VERSION 5.7 ;
  NOWIREEXTENSIONATPIN ON ;
  DIVIDERCHAR "/" ;
  BUSBITCHARS "[]" ;
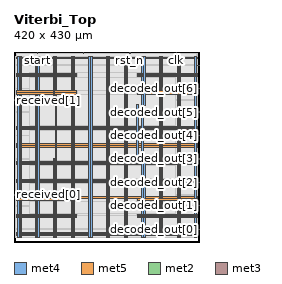
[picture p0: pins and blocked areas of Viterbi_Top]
MACRO Viterbi_Top
  CLASS BLOCK ;
  FOREIGN Viterbi_Top ;
  ORIGIN 0.000 0.000 ;
  SIZE 420.000 BY 430.000 ;
  PIN VGND
    DIRECTION INOUT ;
    USE GROUND ;
    PORT
      LAYER met4 ;
        RECT 13.720 10.640 16.720 419.120 ;
    END
    PORT
      LAYER met4 ;
        RECT 53.720 10.640 56.720 419.120 ;
    END
    PORT
      LAYER met4 ;
        RECT 93.720 10.640 96.720 419.120 ;
    END
    PORT
      LAYER met4 ;
        RECT 133.720 10.640 136.720 419.120 ;
    END
    PORT
      LAYER met4 ;
        RECT 173.720 10.640 176.720 419.120 ;
    END
    PORT
      LAYER met4 ;
        RECT 213.720 10.640 216.720 419.120 ;
    END
    PORT
      LAYER met4 ;
        RECT 253.720 10.640 256.720 419.120 ;
    END
    PORT
      LAYER met4 ;
        RECT 293.720 10.640 296.720 189.380 ;
    END
    PORT
      LAYER met4 ;
        RECT 293.720 308.540 296.720 419.120 ;
    END
    PORT
      LAYER met4 ;
        RECT 333.720 10.640 336.720 419.120 ;
    END
    PORT
      LAYER met4 ;
        RECT 373.720 10.640 376.720 419.120 ;
    END
    PORT
      LAYER met5 ;
        RECT 5.280 19.080 414.700 22.080 ;
    END
    PORT
      LAYER met5 ;
        RECT 5.280 59.080 141.420 62.080 ;
    END
    PORT
      LAYER met5 ;
        RECT 5.280 99.080 414.700 102.080 ;
    END
    PORT
      LAYER met5 ;
        RECT 5.280 139.080 414.700 142.080 ;
    END
    PORT
      LAYER met5 ;
        RECT 5.280 179.080 414.700 182.080 ;
    END
    PORT
      LAYER met5 ;
        RECT 5.280 219.080 414.700 222.080 ;
    END
    PORT
      LAYER met5 ;
        RECT 5.280 259.080 414.700 262.080 ;
    END
    PORT
      LAYER met5 ;
        RECT 5.280 339.080 141.420 342.080 ;
    END
    PORT
      LAYER met5 ;
        RECT 5.280 379.080 141.420 382.080 ;
    END
    PORT
      LAYER met5 ;
        RECT 278.400 59.080 414.700 62.080 ;
    END
    PORT
      LAYER met5 ;
        RECT 278.400 339.080 414.700 342.080 ;
    END
    PORT
      LAYER met5 ;
        RECT 278.400 379.080 414.700 382.080 ;
    END
    PORT
      LAYER met4 ;
        RECT 277.720 184.720 280.720 310.320 ;
    END
  END VGND
  PIN VPWR
    DIRECTION INOUT ;
    USE POWER ;
    PORT
      LAYER met4 ;
        RECT 9.020 10.640 12.020 419.120 ;
    END
    PORT
      LAYER met4 ;
        RECT 49.020 10.640 52.020 419.120 ;
    END
    PORT
      LAYER met4 ;
        RECT 89.020 10.640 92.020 189.380 ;
    END
    PORT
      LAYER met4 ;
        RECT 89.020 308.540 92.020 419.120 ;
    END
    PORT
      LAYER met4 ;
        RECT 129.020 10.640 132.020 419.120 ;
    END
    PORT
      LAYER met4 ;
        RECT 169.020 10.640 172.020 419.120 ;
    END
    PORT
      LAYER met4 ;
        RECT 209.020 10.640 212.020 419.120 ;
    END
    PORT
      LAYER met4 ;
        RECT 249.020 10.640 252.020 419.120 ;
    END
    PORT
      LAYER met4 ;
        RECT 289.020 10.640 292.020 419.120 ;
    END
    PORT
      LAYER met4 ;
        RECT 329.020 10.640 332.020 419.120 ;
    END
    PORT
      LAYER met4 ;
        RECT 369.020 10.640 372.020 419.120 ;
    END
    PORT
      LAYER met4 ;
        RECT 409.020 10.640 412.020 419.120 ;
    END
    PORT
      LAYER met5 ;
        RECT 5.280 14.380 414.700 17.380 ;
    END
    PORT
      LAYER met5 ;
        RECT 5.280 54.380 141.420 57.380 ;
    END
    PORT
      LAYER met5 ;
        RECT 5.280 94.380 141.420 97.380 ;
    END
    PORT
      LAYER met5 ;
        RECT 5.280 134.380 414.700 137.380 ;
    END
    PORT
      LAYER met5 ;
        RECT 5.280 174.380 414.700 177.380 ;
    END
    PORT
      LAYER met5 ;
        RECT 5.280 214.380 414.700 217.380 ;
    END
    PORT
      LAYER met5 ;
        RECT 5.280 254.380 414.700 257.380 ;
    END
    PORT
      LAYER met5 ;
        RECT 5.280 334.380 141.420 337.380 ;
    END
    PORT
      LAYER met5 ;
        RECT 5.280 374.380 141.420 377.380 ;
    END
    PORT
      LAYER met5 ;
        RECT 5.280 414.380 414.700 417.380 ;
    END
    PORT
      LAYER met5 ;
        RECT 278.400 54.380 414.700 57.380 ;
    END
    PORT
      LAYER met5 ;
        RECT 278.400 94.380 414.700 97.380 ;
    END
    PORT
      LAYER met5 ;
        RECT 278.400 334.380 414.700 337.380 ;
    END
    PORT
      LAYER met5 ;
        RECT 278.400 374.380 414.700 377.380 ;
    END
  END VPWR
  PIN clk
    DIRECTION INPUT ;
    USE SIGNAL ;
    ANTENNAGATEAREA 1.286700 ;
    ANTENNADIFFAREA 0.434700 ;
    PORT
      LAYER met2 ;
        RECT 367.170 426.000 367.450 430.000 ;
    END
  END clk
  PIN decoded_out[0]
    DIRECTION OUTPUT ;
    USE SIGNAL ;
    ANTENNADIFFAREA 0.445500 ;
    PORT
      LAYER met3 ;
        RECT 416.000 28.600 420.000 29.200 ;
    END
  END decoded_out[0]
  PIN decoded_out[1]
    DIRECTION OUTPUT ;
    USE SIGNAL ;
    ANTENNADIFFAREA 0.445500 ;
    PORT
      LAYER met3 ;
        RECT 416.000 81.640 420.000 82.240 ;
    END
  END decoded_out[1]
  PIN decoded_out[2]
    DIRECTION OUTPUT ;
    USE SIGNAL ;
    ANTENNADIFFAREA 0.445500 ;
    PORT
      LAYER met3 ;
        RECT 416.000 134.680 420.000 135.280 ;
    END
  END decoded_out[2]
  PIN decoded_out[3]
    DIRECTION OUTPUT ;
    USE SIGNAL ;
    ANTENNADIFFAREA 0.445500 ;
    PORT
      LAYER met3 ;
        RECT 416.000 187.720 420.000 188.320 ;
    END
  END decoded_out[3]
  PIN decoded_out[4]
    DIRECTION OUTPUT ;
    USE SIGNAL ;
    ANTENNADIFFAREA 0.445500 ;
    PORT
      LAYER met3 ;
        RECT 416.000 240.760 420.000 241.360 ;
    END
  END decoded_out[4]
  PIN decoded_out[5]
    DIRECTION OUTPUT ;
    USE SIGNAL ;
    ANTENNADIFFAREA 0.445500 ;
    PORT
      LAYER met3 ;
        RECT 416.000 293.800 420.000 294.400 ;
    END
  END decoded_out[5]
  PIN decoded_out[6]
    DIRECTION OUTPUT ;
    USE SIGNAL ;
    ANTENNADIFFAREA 0.445500 ;
    PORT
      LAYER met3 ;
        RECT 416.000 346.840 420.000 347.440 ;
    END
  END decoded_out[6]
  PIN decoded_out[7]
    DIRECTION OUTPUT ;
    USE SIGNAL ;
    ANTENNADIFFAREA 0.445500 ;
    PORT
      LAYER met3 ;
        RECT 416.000 399.880 420.000 400.480 ;
    END
  END decoded_out[7]
  PIN frame_done
    DIRECTION OUTPUT ;
    USE SIGNAL ;
    ANTENNADIFFAREA 0.445500 ;
    PORT
      LAYER met2 ;
        RECT 157.410 426.000 157.690 430.000 ;
    END
  END frame_done
  PIN received[0]
    DIRECTION INPUT ;
    USE SIGNAL ;
    ANTENNAGATEAREA 0.631200 ;
    ANTENNADIFFAREA 0.434700 ;
    PORT
      LAYER met3 ;
        RECT 0.000 106.120 4.000 106.720 ;
    END
  END received[0]
  PIN received[1]
    DIRECTION INPUT ;
    USE SIGNAL ;
    ANTENNAGATEAREA 0.631200 ;
    ANTENNADIFFAREA 0.434700 ;
    PORT
      LAYER met3 ;
        RECT 0.000 321.000 4.000 321.600 ;
    END
  END received[1]
  PIN rst_n
    DIRECTION INPUT ;
    USE SIGNAL ;
    ANTENNAGATEAREA 0.593700 ;
    ANTENNADIFFAREA 0.434700 ;
    PORT
      LAYER met2 ;
        RECT 262.290 426.000 262.570 430.000 ;
    END
  END rst_n
  PIN start
    DIRECTION INPUT ;
    USE SIGNAL ;
    ANTENNAGATEAREA 0.560700 ;
    ANTENNADIFFAREA 0.434700 ;
    PORT
      LAYER met2 ;
        RECT 52.530 426.000 52.810 430.000 ;
    END
  END start
  OBS
      LAYER nwell ;
        RECT 5.330 10.795 414.650 418.965 ;
      LAYER li1 ;
        RECT 5.520 10.795 414.460 418.965 ;
      LAYER met1 ;
        RECT 5.520 10.640 414.460 427.000 ;
      LAYER met2 ;
        RECT 6.070 425.720 52.250 427.030 ;
        RECT 53.090 425.720 157.130 427.030 ;
        RECT 157.970 425.720 262.010 427.030 ;
        RECT 262.850 425.720 366.890 427.030 ;
        RECT 367.730 425.720 412.530 427.030 ;
        RECT 6.070 10.695 412.530 425.720 ;
      LAYER met3 ;
        RECT 4.000 400.880 416.000 419.045 ;
        RECT 4.000 399.480 415.600 400.880 ;
        RECT 4.000 347.840 416.000 399.480 ;
        RECT 4.000 346.440 415.600 347.840 ;
        RECT 4.000 322.000 416.000 346.440 ;
        RECT 4.400 320.600 416.000 322.000 ;
        RECT 4.000 294.800 416.000 320.600 ;
        RECT 4.000 293.400 415.600 294.800 ;
        RECT 4.000 241.760 416.000 293.400 ;
        RECT 4.000 240.360 415.600 241.760 ;
        RECT 4.000 188.720 416.000 240.360 ;
        RECT 4.000 187.320 415.600 188.720 ;
        RECT 4.000 135.680 416.000 187.320 ;
        RECT 4.000 134.280 415.600 135.680 ;
        RECT 4.000 107.120 416.000 134.280 ;
        RECT 4.400 105.720 416.000 107.120 ;
        RECT 4.000 82.640 416.000 105.720 ;
        RECT 4.000 81.240 415.600 82.640 ;
        RECT 4.000 29.600 416.000 81.240 ;
        RECT 4.000 28.200 415.600 29.600 ;
        RECT 4.000 10.715 416.000 28.200 ;
      LAYER met4 ;
        RECT 34.620 59.980 48.620 383.540 ;
        RECT 52.420 59.980 53.320 383.540 ;
        RECT 57.120 308.140 88.620 383.540 ;
        RECT 92.420 308.140 93.320 383.540 ;
        RECT 57.120 189.780 93.320 308.140 ;
        RECT 57.120 59.980 88.620 189.780 ;
        RECT 92.420 59.980 93.320 189.780 ;
        RECT 97.120 59.980 128.620 383.540 ;
        RECT 132.420 59.980 133.320 383.540 ;
        RECT 137.120 59.980 168.620 383.540 ;
        RECT 172.420 59.980 173.320 383.540 ;
        RECT 177.120 59.980 208.620 383.540 ;
        RECT 212.420 59.980 213.320 383.540 ;
        RECT 217.120 59.980 248.620 383.540 ;
        RECT 252.420 59.980 253.320 383.540 ;
        RECT 257.120 310.720 288.620 383.540 ;
        RECT 257.120 184.320 277.320 310.720 ;
        RECT 281.120 184.320 288.620 310.720 ;
        RECT 257.120 59.980 288.620 184.320 ;
        RECT 292.420 308.140 293.320 383.540 ;
        RECT 297.120 308.140 328.620 383.540 ;
        RECT 292.420 189.780 328.620 308.140 ;
        RECT 292.420 59.980 293.320 189.780 ;
        RECT 297.120 59.980 328.620 189.780 ;
        RECT 332.420 59.980 333.320 383.540 ;
        RECT 337.120 59.980 365.180 383.540 ;
      LAYER met5 ;
        RECT 143.020 372.780 276.800 383.540 ;
        RECT 34.620 343.680 365.180 372.780 ;
        RECT 143.020 332.780 276.800 343.680 ;
        RECT 34.620 263.680 365.180 332.780 ;
        RECT 34.620 223.680 365.180 252.780 ;
        RECT 34.620 183.680 365.180 212.780 ;
        RECT 34.620 143.680 365.180 172.780 ;
        RECT 34.620 103.680 365.180 132.780 ;
        RECT 143.020 92.780 276.800 97.480 ;
        RECT 34.620 63.680 365.180 92.780 ;
        RECT 143.020 59.980 276.800 63.680 ;
  END
END Viterbi_Top
END LIBRARY

